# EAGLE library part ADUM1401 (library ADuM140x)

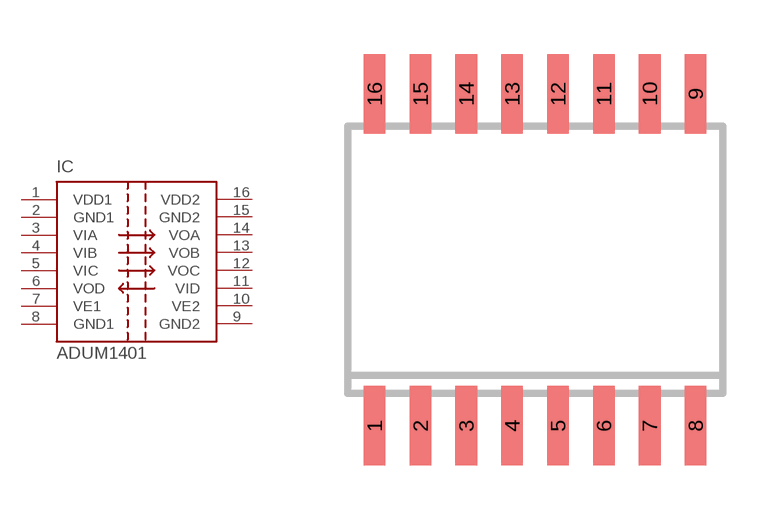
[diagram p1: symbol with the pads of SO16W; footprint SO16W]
Designator prefix IC

## ADUM1401  [SO16W]
1  VDD1  pwr
2  GND1  sup
3  VIA  in
4  VIB  in
5  VIC  in
6  VOD  out
7  VE1  pas
8  GND1  sup
9  GND2  sup
10  VE2  pas
11  VID  in
12  VOC  out
13  VOB  out
14  VOA  out
15  GND2  sup
16  VDD2  pwr

## Footprint SO16W (pad centres in mm)
SMALL OUTLINE INTEGRATED CIRCUIT wide body 7.5 mm/JEDEC MS-013AA
smd 0.6 x 2.2: 1 -4.445,-4.6; 2 -3.175,-4.6; 3 -1.905,-4.6; 4 -0.635,-4.6; 5 0.635,-4.6; 6 1.905,-4.6; 7 3.175,-4.6; 8 4.445,-4.6; 9 4.445,4.6; 10 3.175,4.6; 11 1.905,4.6; 12 0.635,4.6; 13 -0.635,4.6; 14 -1.905,4.6; 15 -3.175,4.6; 16 -4.445,4.6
